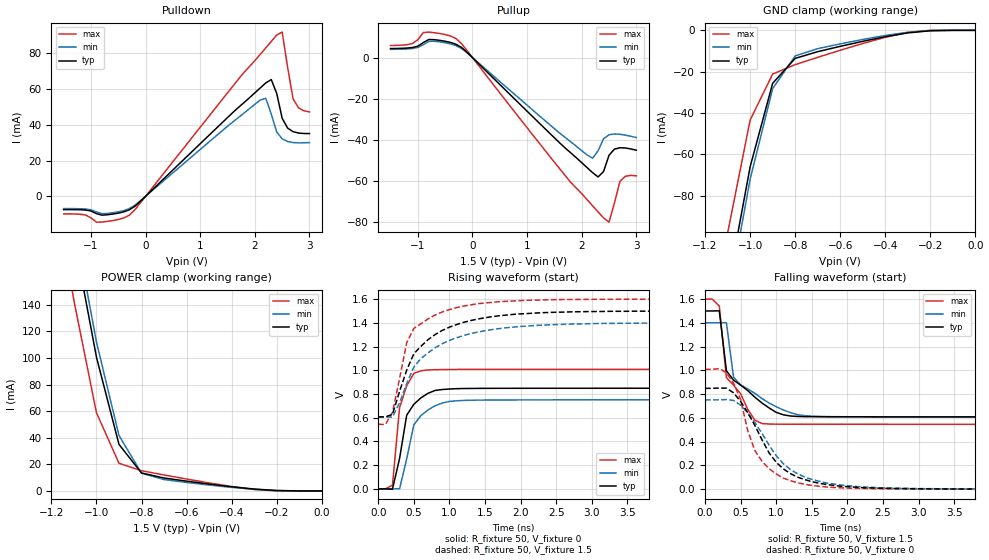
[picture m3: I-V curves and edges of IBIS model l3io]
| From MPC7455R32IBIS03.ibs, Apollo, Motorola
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| *   l3io Model   *
[Model]   l3io
Model_type   I/O
Polarity   Non-Inverting
Vinl = 0.53V
Vinh = 0.98V
Vmeas = 0.75V
Cref = 0
Rref = 50
Vref = 0.75V
|   typ   min   max
C_comp   5.904767e-12   4.680024e-12   6.281383e-12
|   typ   min   max
[Voltage range]   1.5V   1.4V   1.6V
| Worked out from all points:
|   slope of the pulldown table from 0 to 0.225 V, typ, clamps not added: 33.9 ohm
|   slope of the pullup table from 0 to 0.225 V, typ, clamps not added: 38.2 ohm
|   GND clamp passes 1 mA (typ) near -0.28 V on its own axis
|   POWER clamp passes 1 mA (typ) near -0.26 V on its own axis
|   falling waveform, R_fixture 50, V_fixture 1.5: 20-80 % time 443ps typ, 460ps min, 310ps max; typ from 1.5 V to 0.607 V
|   rising waveform, R_fixture 50, V_fixture 0: 20-80 % time 196ps typ, 219ps min, 140ps max; typ from 0.001 V to 0.849 V
|   falling waveform, R_fixture 50, V_fixture 0: 20-80 % time 539ps typ, 593ps min, 392ps max; typ from 0.849 V to 0.001 V
|   rising waveform, R_fixture 50, V_fixture 1.5: 20-80 % time 577ps typ, 638ps min, 353ps max; typ from 0.607 V to 1.5 V
[Pulldown]
|   Voltage   I(typ)   I(min)   I(max)
-1.5V     -7.483mA   -6.928mA   -9.894mA
-1.1V     -7.726mA   -7.136mA   -10.5mA
-900mV    -9.737mA   -8.748mA   -14.53mA
-300mV    -7.614mA   -6.96mA    -10.65mA
2.1V      60.71mA    53.91mA    79.48mA
2.2V      63.47mA    54.85mA    83.09mA
2.3V      65.35mA    46.04mA    86.71mA
2.4V      57.58mA    35.97mA    90.29mA
2.5V      43.66mA    32.13mA    91.94mA
2.7V      36.18mA    30.08mA    54.51mA
2.8V      35.4mA     29.89mA    49.5mA
3V        35.13mA    30.06mA    47.22mA
[GND_clamp]
-1.5V     -404.1mA   -411.4mA   -383.8mA
-1.1V     -125mA     -132mA     -98.23mA
-1V       -66.08mA   -72.12mA   -43.43mA
-900mV    -25.63mA   -28.18mA   -21.18mA
-800mV    -13.57mA   -12.38mA   -16.61mA
-700mV    -10.33mA   -8.868mA   -13.07mA
-600mV    -7.752mA   -6.552mA   -9.651mA
-400mV    -3.085mA   -2.482mA   -3.365mA
-300mV    -1.241mA   -938.8uA   -989uA
-200mV    -201.8uA   -143uA     0A
0V        0A         0A         0A
[Pullup]
-1.5V     4.378mA    3.977mA    5.857mA
-1.1V     4.875mA    4.402mA    6.82mA
-900mV    7.285mA    6.276mA    12.15mA
-700mV    8.69mA     7.905mA    12.08mA
-300mV    6.439mA    5.797mA    9.216mA
2.1V      -53.49mA   -47.34mA   -69.04mA
2.2V      -55.92mA   -48.87mA   -72.01mA
2.3V      -57.99mA   -45.31mA   -74.97mA
2.4V      -55.37mA   -39.49mA   -77.89mA
2.5V      -47.47mA   -37.5mA    -79.97mA
2.7V      -43.81mA   -37.27mA   -60.17mA
3V        -45.01mA   -38.85mA   -57.44mA
[POWER_clamp]
-1.5V     610.6mA    623.8mA    569.3mA
-1.2V     290.7mA    303.7mA    243.4mA
-1.1V     190.9mA    203.6mA    143.2mA
-1V       100.6mA    112.1mA    58.83mA
-900mV    35.01mA    41.7mA     20.8mA
-800mV    13.49mA    13.36mA    15.22mA
-700mV    9.705mA    8.546mA    12.01mA
-500mV    5.163mA    4.442mA    6.014mA
-300mV    1.418mA    1.193mA    1.109mA
-200mV    313.2uA    265.8uA    0A
0V        0A         0A         0A
|   typ   min   max
[Ramp]
dV/dt_r   0.50891/1.65796e-10   0.45048/1.90002e-10   0.60527/1.39510e-10
dV/dt_f   0.53553/4.10203e-10   0.47584/4.39258e-10   0.63292/3.31736e-10
[Falling Waveform]
R_fixture = 50
V_fixture = 1.5
V_fixture_min = 1.4
V_fixture_max = 1.6
| time   V(typ)   V(min)   V(max)
0s        1.5V       1.4V       1.6V
100ps     1.5V       1.4V       1.6V
200ps     1.501V     1.4V       1.541V
300ps     996.2mV    1.401V     938.6mV
400ps     917.9mV    942.3mV    875.8mV
700ps     774.2mV    806.4mV    580.9mV
800ps     725.5mV    763.2mV    552.7mV
1.1ns     626.4mV    666.7mV    547mV
1.7ns     609.8mV    611.3mV    546.6mV
19.7ns    607.4mV    606.9mV    545.2mV
[Rising Waveform]
R_fixture = 50
V_fixture = 0
V_fixture_min = 0
V_fixture_max = 0
| time   V(typ)   V(min)   V(max)
0s        628.8uV    569.2uV    558.4uV
100ps     611.5uV    579.3uV    695.4uV
200ps     -1.779mV   695.6uV    31.64mV
300ps     256.7mV    1.067mV    686.3mV
400ps     621.6mV    253.7mV    869.2mV
500ps     712.9mV    539.9mV    973.3mV
700ps     806.1mV    666.2mV    1.003V
1ns       842mV      737.1mV    1.007V
1.5ns     847.6mV    749.1mV    1.008V
19.7ns    848.8mV    751.4mV    1.009V
[Falling Waveform]
R_fixture = 50
V_fixture = 0
V_fixture_min = 0
V_fixture_max = 0
| time   V(typ)   V(min)   V(max)
0s        848.8mV    751.4mV    1.009V
200ps     851.4mV    752mV      1.015V
400ps     811.4mV    747.2mV    893.2mV
500ps     738.4mV    707mV      752.7mV
600ps     644.6mV    641mV      492.5mV
700ps     537mV      560.5mV    325.4mV
900ps     305.4mV    370.5mV    172.8mV
1.2ns     131.9mV    165.9mV    72.32mV
1.7ns     40.46mV    53.61mV    18.94mV
19.7ns    602.3uV    526.5uV    573.3uV
[Rising Waveform]
R_fixture = 50
V_fixture = 1.5
V_fixture_min = 1.4
V_fixture_max = 1.6
| time   V(typ)   V(min)   V(max)
0s        607.4mV    606.9mV    545.1mV
100ps     607mV      606.9mV    542.6mV
200ps     628.8mV    604.6mV    644.3mV
400ps     1.001V     888.2mV    1.232V
500ps     1.139V     1.027V     1.352V
700ps     1.258V     1.147V     1.433V
1ns       1.363V     1.252V     1.511V
1.7ns     1.459V     1.351V     1.578V
3.8ns     1.498V     1.398V     1.599V
19.7ns    1.5V       1.4V       1.6V
